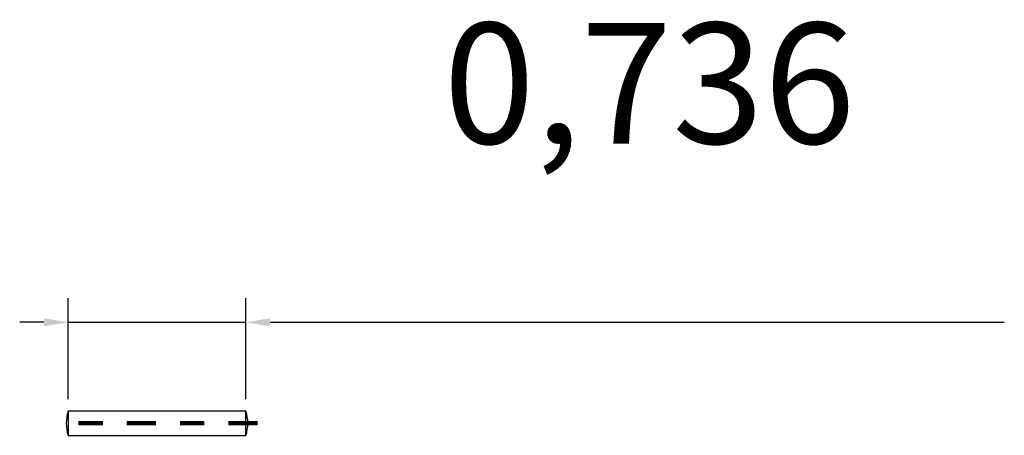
# Model space of a CAD drawing. Units: millimetres. Extents: x -0.2 to 3.87, y -0.05 to 1.67.
import ezdxf

# ---------------------------------------------------------------- set-up
doc = ezdxf.new("R2010")
doc.units = ezdxf.units.MM
doc.header["$LTSCALE"] = 0.01
doc.linetypes.add('ACAD_ISO10W100', pattern=[18, 12, -3, 0, -3])
doc.styles.get("Standard").update_dxf_attribs({"font": 'ARIAL.TTF', "height": 0.5})
doc.dimstyles.new('ISO-25', dxfattribs={"dimtxt": 0.1, "dimasz": 0.1, "dimexe": 0.1, "dimexo": 0.05, "dimtad": 1, "dimdec": 4, "dimtxsty": 'Standard', "dimcen": 0.1, "dimadec": 0, "dimazin": 0, "dimtfac": 1, "dimtdec": 4, "dimtmove": 0, "dimatfit": 3, "dimfxl": 0, "dimarcsym": 0})

# ---------------------------------------------------------------- blocks, each defined once
blk = doc.blocks.new('*D4')
at = {"color": 0, "lineweight": -2}
for p, q in [((0, 0.1), (0, 0.5182)), ((0.736, 0.1), (0.736, 0.5182)), ((-0.1, 0.4182), (-0.2, 0.4182)), ((0, 0.4182), (0.736, 0.4182)), ((0.836, 0.4182), (3.8729, 0.4182))]:
    blk.add_line(p, q, dxfattribs=at)
at = {"color": 0, "lineweight": 100}
for points in [[(-0.1, 0.4349), (-0.1, 0.4016), (0, 0.4182)], [(0.836, 0.4349), (0.836, 0.4016), (0.736, 0.4182)]]:
    blk.add_solid(points, dxfattribs=at)
at = {"layer": 'Defpoints', "color": 0, "lineweight": 100}
for p in [(0.736, 0.4182), (0, 0.05), (0.736, 0.05)]:
    blk.add_point(p, dxfattribs=at)
at = {"color": 0, "lineweight": 100, "insert": (2.4045, 1.3437), "char_height": 0.5, "attachment_point": 5}
blk.add_mtext('0,736', dxfattribs=at)

msp = doc.modelspace()

# ---------------------------------------------------------------- linework, layer by layer
for p, q in [((0, 0.05), (0, -0.05)), ((0.736, 0.05), (0, 0.05)), ((0.736, -0.05), (0.736, 0.05)), ((0, -0.05), (0.736, -0.05))]:
    msp.add_line(p, q)
at = {"color": 1, "linetype": 'ACAD_ISO10W100', "lineweight": 100}
msp.add_line((0.78341, 0), (-0.0279, 0), dxfattribs=at)
for centre, start, end in [((0.16292, 0), 162.93847, 197.06153), ((0.57308, 0), 342.93847, 17.06153)]:
    msp.add_arc(centre, 0.17042, start, end)

# ---------------------------------------------------------------- dimensions: what is measured, and where the dimension line sits
at = {"color": 7, "lineweight": 100}
dim = msp.add_linear_dim(base=(0.736, 0.41825), p1=(0, 0.05), p2=(0.736, 0.05), dimstyle='ISO-25', dxfattribs=at)
dim.commit()
dim.dimension.update_dxf_attribs({"geometry": '*D4', "text_midpoint": (2.40445, 1.34373)})

doc.saveas('drawing.dxf')
